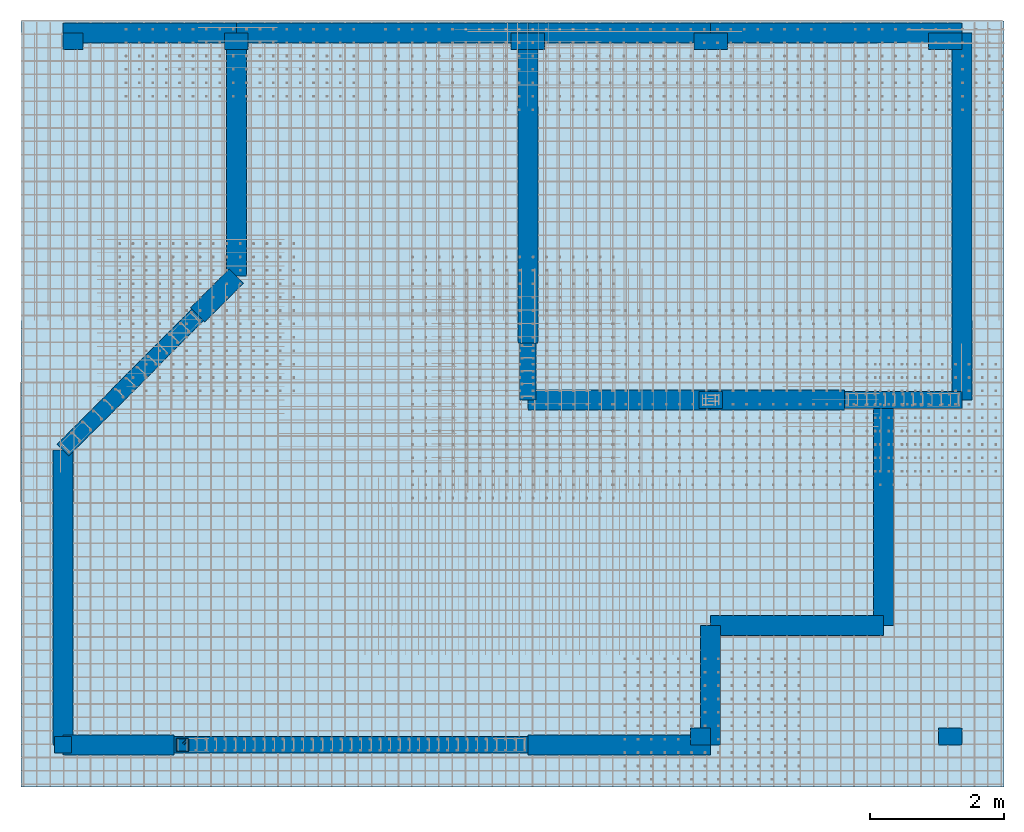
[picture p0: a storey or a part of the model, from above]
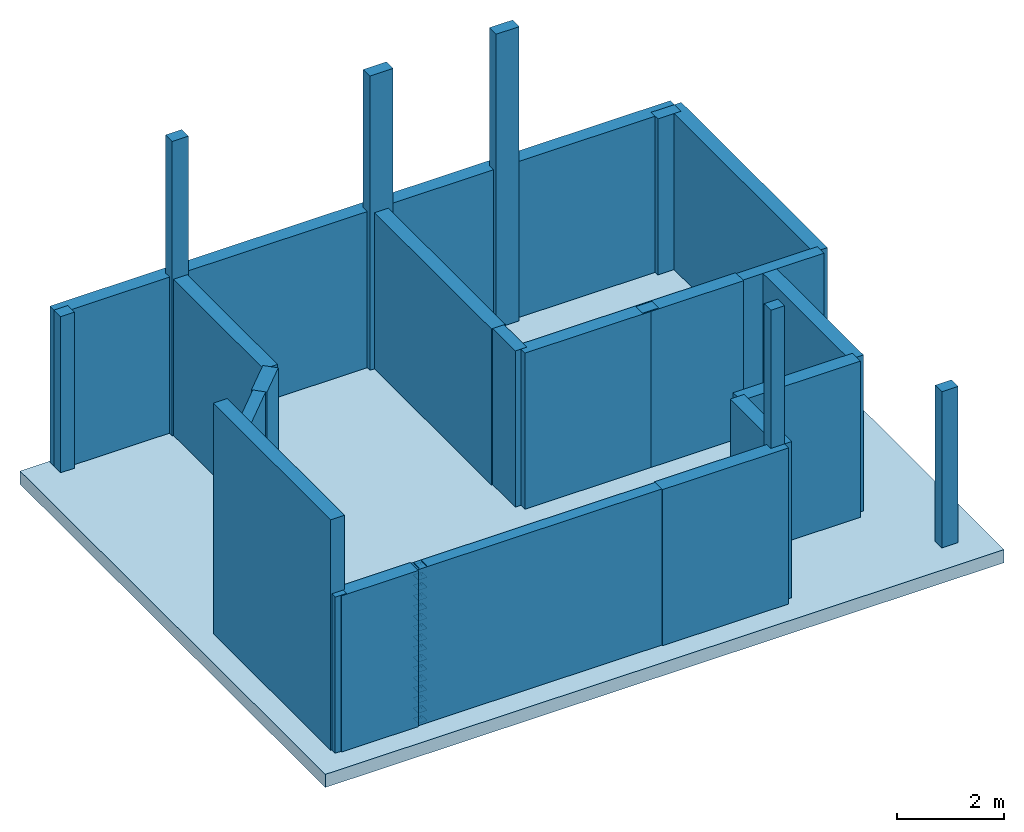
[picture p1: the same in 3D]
Properties of the parts of a building model (IFC4)

# File
Description: ViewDefinition [CoordinationView]
Made in: IFC file generated by ModeSt (Tecnisoft s.a.s.)

# IfcBuildingStorey (3)
In: Abitazione
Name | Elevation (m)
Storey 0 | 0
Storey 1 | 3.57
Storey 2 | 6.73

# IfcBeam: 1 Cr 25x25, 101
In: Storey 1
Type - PredefinedType: BEAM; Material: Calcestruzzo classe C25/30
Description: 1 Cr 25x25 - Cemento armato
Pset_BeamCommon - LoadBearing: yes
BaseQuantities - ?: 0.0625 m2; ?: 0.10375 m3; ?: 1.66 m

# IfcColumn: 2 PL 25x25 principale (2)
Type - PredefinedType: COLUMN; Material: Calcestruzzo classe C25/30
Description: 2 PL 25x25 principale - Cemento armato
Pset_ColumnCommon - LoadBearing: yes
BaseQuantities - ?: 0.0625 m2
Name | In | BaseQuantities, ? (m3) | BaseQuantities, ? (m)
1 | Storey 0 | 0.223125 | 3.57
1 | Storey 1 | 0.106268 | 1.7003

# IfcColumn: 3 PL 25x25 falso (2)
In: Storey 1
Type - PredefinedType: COLUMN; Material: Calcestruzzo classe C25/30
Description: 3 PL 25x25 falso - Cemento armato
Pset_ColumnCommon - LoadBearing: yes
BaseQuantities - ?: 0.0625 m2; ?: 0.1975 m3; ?: 3.16 m
Name
4
6

# IfcColumn: 4 PL 25x30 principale (3)
Type - PredefinedType: COLUMN; Material: Calcestruzzo classe C25/30
Description: 4 PL 25x30 principale - Cemento armato
Pset_ColumnCommon - LoadBearing: yes
BaseQuantities - ?: 0.075 m2
Name | In | BaseQuantities, ? (m3) | BaseQuantities, ? (m)
7 | Storey 0 | 0.26775 | 3.57
2 | Storey 0 | 0.50475 | 6.73
7 | Storey 1 | 0.237 | 3.16

# IfcColumn: 7 PL 25x35 principale (4)
Type - PredefinedType: COLUMN; Material: Calcestruzzo classe C25/30
Description: 7 PL 25x35 principale - Cemento armato
Pset_ColumnCommon - LoadBearing: yes
BaseQuantities - ?: 0.0875 m2
Name | In | BaseQuantities, ? (m3) | BaseQuantities, ? (m)
5 | Storey 0 | 0.312375 | 3.57
3 | Storey 0 | 0.312375 | 3.57
8 | Storey 0 | 0.588875 | 6.73
3 | Storey 1 | 0.2765 | 3.16

# IfcColumn: 8 PL 25x50 principale (4)
Type - PredefinedType: COLUMN; Material: Calcestruzzo classe C25/30
Description: 8 PL 25x50 principale - Cemento armato
Pset_ColumnCommon - LoadBearing: yes
BaseQuantities - ?: 0.125 m2
Name | In | BaseQuantities, ? (m3) | BaseQuantities, ? (m)
11 | Storey 0 | 0.44625 | 3.57
10 | Storey 0 | 0.84125 | 6.73
9 | Storey 0 | 0.84125 | 6.73
11 | Storey 1 | 0.395 | 3.16

# IfcFooting: 1 Platea 30
In: Storey 0
Type - PredefinedType: STRIP_FOOTING
Description: 1 Platea 30; Material: Calcestruzzo classe C25/30 0.3 m
Pset_WallCommon - LoadBearing: yes
BaseQuantities - ?: 50.3818 m3

# IfcReinforcingBar (232)
SteelGrade: B450C
Name | In | NominalDiameter (m) | CrossSectionArea (m2) | BarLength (m)
4 x  | Storey 0 | 0.012 | 0.0001131 | 3.545
3 x  | Storey 0 | 0.012 | 0.0001131 | 0.861822
 | Storey 0 | 0.01 | 0.00007854 | 2.78965
2 x  | Storey 0 | 0.01 | 0.00007854 | 1.16122
 | Storey 0 | 0.01 | 0.00007854 | 5.22
2 x  | Storey 0 | 0.01 | 0.00007854 | 1.16121
 | Storey 0 | 0.016 | 0.00020106 | 3.738
 | Storey 0 | 0.016 | 0.00020106 | 0.857429
 | Storey 0 | 0.01 | 0.00007854 | 0.981776
 | Storey 0 | 0.012 | 0.0001131 | 0.861821
 | Storey 0 | 0.01 | 0.00007854 | 0.79
 | Storey 0 | 0.01 | 0.00007854 | 1.69
3 x  | Storey 1 | 0.012 | 0.0001131 | 3.135
3 x  | Storey 1 | 0.012 | 0.0001131 | 0.811821
 | Storey 1 | 0.012 | 0.0001131 | 1.6753
 | Storey 1 | 0.01 | 0.00007854 | 2.78965
2 x  | Storey 1 | 0.01 | 0.00007854 | 1.16122
 | Storey 1 | 0.01 | 0.00007854 | 1.73161
 | Storey 1 | 0.012 | 0.0001131 | 3.12101
 | Storey 1 | 0.012 | 0.0001131 | 3.09064
 | Storey 1 | 0.012 | 0.0001131 | 3.06027
 | Storey 1 | 0.012 | 0.0001131 | 3.0299
 | Storey 1 | 0.012 | 0.0001131 | 2.99953
 | Storey 1 | 0.012 | 0.0001131 | 2.96916
 | Storey 1 | 0.012 | 0.0001131 | 2.93879
 | Storey 1 | 0.012 | 0.0001131 | 2.90842
 | Storey 1 | 0.012 | 0.0001131 | 2.87805
 | Storey 1 | 0.012 | 0.0001131 | 2.84768
 | Storey 1 | 0.012 | 0.0001131 | 2.81731
 | Storey 1 | 0.012 | 0.0001131 | 2.78694
 | Storey 1 | 0.012 | 0.0001131 | 2.75657
 | Storey 1 | 0.012 | 0.0001131 | 2.7262
 | Storey 1 | 0.012 | 0.0001131 | 2.69583
 | Storey 1 | 0.012 | 0.0001131 | 2.66546
 | Storey 1 | 0.012 | 0.0001131 | 2.63509
 | Storey 1 | 0.012 | 0.0001131 | 2.60472
 | Storey 1 | 0.012 | 0.0001131 | 2.57435
 | Storey 1 | 0.012 | 0.0001131 | 2.54398
 | Storey 1 | 0.012 | 0.0001131 | 2.51361
 | Storey 1 | 0.012 | 0.0001131 | 2.48324
 | Storey 1 | 0.012 | 0.0001131 | 2.45288
 | Storey 1 | 0.012 | 0.0001131 | 2.42251
 | Storey 1 | 0.012 | 0.0001131 | 2.39214
 | Storey 1 | 0.012 | 0.0001131 | 2.36177
 | Storey 1 | 0.012 | 0.0001131 | 2.3314
 | Storey 1 | 0.012 | 0.0001131 | 2.30103
 | Storey 1 | 0.012 | 0.0001131 | 2.27066
 | Storey 1 | 0.012 | 0.0001131 | 2.24029
 | Storey 1 | 0.012 | 0.0001131 | 2.20992
 | Storey 1 | 0.012 | 0.0001131 | 2.17955
 | Storey 1 | 0.012 | 0.0001131 | 2.14918
 | Storey 1 | 0.012 | 0.0001131 | 2.11881
 | Storey 1 | 0.012 | 0.0001131 | 2.08844
 | Storey 1 | 0.012 | 0.0001131 | 2.05807
 | Storey 1 | 0.01 | 0.00007854 | 5.22
 | Storey 1 | 0.01 | 0.00007854 | 1.16121
 | Storey 1 | 0.01 | 0.00007854 | 4.52613
 | Storey 1 | 0.01 | 0.00007854 | 3.39239
 | Storey 1 | 0.01 | 0.00007854 | 2.25865
 | Storey 1 | 0.01 | 0.00007854 | 1.12491
 | Storey 1 | 0.01 | 0.00007854 | 0.79
2 x  | Storey 1 | 0.02 | 0.00031416 | 1.22254
 | Storey 1 | 0.02 | 0.00031416 | 4.78761
 | Storey 1 | 0.016 | 0.00020106 | 1.68472
 | Storey 1 | 0.006 | 0.000028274 | 0.887811
 | Storey 1 | 0.008 | 0.000050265 | 0.898837
6 x  | Storey 1 | 0.022 | 0.00038013 | 1.30034
 | Storey 1 | 0.016 | 0.00020106 | 1.30693
6 x  | Storey 1 | 0.022 | 0.00038013 | 4.45
 | Storey 1 | 0.016 | 0.00020106 | 4.45
 | Storey 1 | 0.022 | 0.00038013 | 3.26284
 | Storey 1 | 0.006 | 0.000028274 | 0.987803
 | Storey 1 | 0.006 | 0.000028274 | 0.402429
 | Storey 1 | 0.02 | 0.00031416 | 4.37
7 x  | Storey 1 | 0.02 | 0.00031416 | 3.26504
 | Storey 1 | 0.008 | 0.000050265 | 0.408429
 | Storey 1 | 0.008 | 0.000050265 | 1.09882
 | Storey 1 | 0.006 | 0.000028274 | 0.773178
2 x  | Storey 1 | 0.006 | 0.000028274 | 1.0878
2 x  | Storey 1 | 0.02 | 0.00031416 | 1.17254
2 x  | Storey 1 | 0.008 | 0.000050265 | 0.898838
 | Storey 0 | 0.02 | 0.00031416 | 1.22254
 | Storey 0 | 0.02 | 0.00031416 | 3.67504
 | Storey 0 | 0.006 | 0.000028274 | 1.0878
4 x  | Storey 1 | 0.016 | 0.00020106 | 3.26943
 | Storey 1 | 0.006 | 0.000028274 | 0.987804
4 x  | Storey 1 | 0.006 | 0.000028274 | 0.40243
3 x  | Storey 1 | 0.006 | 0.000028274 | 1.38779
3 x  | Storey 1 | 0.006 | 0.000028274 | 0.875812
 | Storey 0 | 0.012 | 0.0001131 | 15.0672
 | Storey 0 | 0.012 | 0.0001131 | 11.8272
 | Storey 0 | 0.012 | 0.0001131 | 1.79591
 | Storey 0 | 0.012 | 0.0001131 | 0.437045
 | Storey 0 | 0.012 | 0.0001131 | 3.42591
 | Storey 0 | 0.012 | 0.0001131 | 1.77591
 | Storey 0 | 0.012 | 0.0001131 | 0.995909
 | Storey 0 | 0.012 | 0.0001131 | 1.94591
 | Storey 0 | 0.012 | 0.0001131 | 1.18591
 | Storey 0 | 0.012 | 0.0001131 | 0.915909
 | Storey 0 | 0.012 | 0.0001131 | 1.42591
 | Storey 0 | 0.012 | 0.0001131 | 4.09591
 | Storey 0 | 0.012 | 0.0001131 | 1.45505
 | Storey 0 | 0.012 | 0.0001131 | 1.92591
 | Storey 0 | 0.016 | 0.00020106 | 2.18455
 | Storey 0 | 0.016 | 0.00020106 | 0.582727
 | Storey 0 | 0.012 | 0.0001131 | 1.91591
 | Storey 0 | 0.01 | 0.00007854 | 0.21
 | Storey 0 | 0.03 | 0.00070686 | 0.005
 | Storey 0 | 0.012 | 0.0001131 | 2.57463
 | Storey 0 | 0.012 | 0.0001131 | 1.76232
 | Storey 1 | 0.012 | 0.0001131 | 6.76721
 | Storey 1 | 0.012 | 0.0001131 | 0.496173
 | Storey 1 | 0.012 | 0.0001131 | 0.695183
 | Storey 1 | 0.012 | 0.0001131 | 0.894192
 | Storey 1 | 0.012 | 0.0001131 | 13.7072
 | Storey 1 | 0.012 | 0.0001131 | 6.50716
 | Storey 1 | 0.012 | 0.0001131 | 6.30617
 | Storey 1 | 0.012 | 0.0001131 | 6.10517
 | Storey 1 | 0.012 | 0.0001131 | 5.90418
 | Storey 1 | 0.012 | 0.0001131 | 5.76721
 | Storey 1 | 0.012 | 0.0001131 | 10.9172
 | Storey 1 | 0.012 | 0.0001131 | 0.73963
 | Storey 1 | 0.012 | 0.0001131 | 0.437046
 | Storey 1 | 0.016 | 0.00020106 | 1.72591
 | Storey 1 | 0.016 | 0.00020106 | 0.582727
 | Storey 1 | 0.016 | 0.00020106 | 0.461142
 | Storey 1 | 0.016 | 0.00020106 | 1.83017
 | Storey 1 | 0.016 | 0.00020106 | 2.99591
 | Storey 1 | 0.012 | 0.0001131 | 1.58591
 | Storey 1 | 0.02 | 0.00031416 | 2.86318
 | Storey 1 | 0.02 | 0.00031416 | 0.728409
 | Storey 1 | 0.016 | 0.00020106 | 0.827482
 | Storey 1 | 0.012 | 0.0001131 | 1.39591
 | Storey 1 | 0.016 | 0.00020106 | 1.30591
 | Storey 1 | 0.016 | 0.00020106 | 1.69591
 | Storey 1 | 0.012 | 0.0001131 | 1.36591
 | Storey 1 | 0.012 | 0.0001131 | 0.424888
 | Storey 1 | 0.012 | 0.0001131 | 0.467344
 | Storey 1 | 0.012 | 0.0001131 | 0.876429
 | Storey 1 | 0.012 | 0.0001131 | 0.462548
 | Storey 1 | 0.016 | 0.00020106 | 0.551757
 | Storey 1 | 0.012 | 0.0001131 | 1.09591
 | Storey 1 | 0.012 | 0.0001131 | 1.61591
 | Storey 1 | 0.012 | 0.0001131 | 0.433676
 | Storey 1 | 0.012 | 0.0001131 | 0.858311
 | Storey 1 | 0.012 | 0.0001131 | 0.476277
 | Storey 1 | 0.012 | 0.0001131 | 0.48324
 | Storey 1 | 0.016 | 0.00020106 | 0.881223
 | Storey 1 | 0.012 | 0.0001131 | 0.471284
 | Storey 1 | 0.012 | 0.0001131 | 0.830613
 | Storey 1 | 0.01 | 0.00007854 | 0.16
 | Storey 1 | 0.03 | 0.00070686 | 0.00499988
 | Storey 1 | 0.012 | 0.0001131 | 2.16321
 | Storey 1 | 0.012 | 0.0001131 | 1.4266
 | Storey 1 | 0.012 | 0.0001131 | 1.52661
 | Storey 1 | 0.012 | 0.0001131 | 1.4766
 | Storey 1 | 0.012 | 0.0001131 | 1.42661
 | Storey 1 | 0.012 | 0.0001131 | 2.36321
 | Storey 1 | 0.012 | 0.0001131 | 1.67661
 | Storey 2 | 0.012 | 0.0001131 | 7.15721
 | Storey 2 | 0.012 | 0.0001131 | 7.61721
 | Storey 2 | 0.012 | 0.0001131 | 14.4872
 | Storey 2 | 0.012 | 0.0001131 | 8.18721
 | Storey 2 | 0.012 | 0.0001131 | 5.98721
 | Storey 2 | 0.012 | 0.0001131 | 6.10721
 | Storey 2 | 0.012 | 0.0001131 | 11.7072
 | Storey 2 | 0.012 | 0.0001131 | 9.88721
 | Storey 2 | 0.012 | 0.0001131 | 1.20721
 | Storey 2 | 0.012 | 0.0001131 | 0.603401
 | Storey 2 | 0.012 | 0.0001131 | 1.06591
 | Storey 2 | 0.012 | 0.0001131 | 0.437046
 | Storey 2 | 0.012 | 0.0001131 | 0.885909
 | Storey 2 | 0.012 | 0.0001131 | 1.12591
 | Storey 2 | 0.012 | 0.0001131 | 1.81395
 | Storey 2 | 0.012 | 0.0001131 | 2.11591
 | Storey 2 | 0.012 | 0.0001131 | 0.815909
 | Storey 2 | 0.012 | 0.0001131 | 0.781222
 | Storey 2 | 0.012 | 0.0001131 | 0.783555
 | Storey 2 | 0.012 | 0.0001131 | 0.785886
 | Storey 2 | 0.012 | 0.0001131 | 0.133206
 | Storey 2 | 0.012 | 0.0001131 | 0.955909
 | Storey 2 | 0.012 | 0.0001131 | 0.387218
 | Storey 2 | 0.01 | 0.00007854 | 0.16
 | Storey 2 | 0.03 | 0.00070686 | 0.00500011
 | Storey 1 | 0.016 | 0.00020106 | 6.20721
 | Storey 1 | 0.012 | 0.0001131 | 8.5871
 | Storey 1 | 0.012 | 0.0001131 | 6.23121
 | Storey 1 | 0.01 | 0.00007854 | 8.6051
 | Storey 1 | 0.008 | 0.000050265 | 0.986828
 | Storey 1 | 0.016 | 0.00020106 | 2.30621

# IfcSlab: 2 Soletta (S01) 25
In: Storey 1
Type - PredefinedType: BASESLAB
Description: 2 Soletta (S01) 25; Material: Calcestruzzo classe C25/30 0.25 m
Pset_WallCommon - LoadBearing: yes
BaseQuantities - ?: 35.6637 m3

# IfcSlab: 4 Soletta (C) 25
In: Storey 2
Type - PredefinedType: BASESLAB
Description: 4 Soletta (C) 25; Material: Calcestruzzo classe C25/30 0.25 m
Pset_WallCommon - LoadBearing: yes
BaseQuantities - ?: 40.541 m3

# IfcSlab: 6 Soletta (C) 25 inclinata
In: Storey 1
Type - PredefinedType: BASESLAB
Description: 6 Soletta (C) 25 inclinata; Material: Calcestruzzo classe C25/30 0.25 m
Pset_WallCommon - LoadBearing: yes
BaseQuantities - ?: 94.9916 m3

# IfcWall (30)
Pset_WallCommon - LoadBearing: yes
Name | In | Material
212 | Storey 0 | TAMP 366
101 | Storey 0 | TAMP 366
102 | Storey 0 | TAMP 366
118 | Storey 0 | TAMP 366
104 | Storey 0 | TAMP 366
119 | Storey 0 | TAMP 366
111 | Storey 0 | TAMP 366
109 | Storey 0 | TAMP 366
108 | Storey 0 | TAMP 366
107 | Storey 0 | TAMP 366
113 | Storey 0 | TAMP 366
112 | Storey 0 | TAMP 366
115 | Storey 0 | TAMP 366
105 | Storey 0 | TAMP 240
114 | Storey 0 | TAMP 240
106 | Storey 0 | TAMP 240
201 | Storey 1 | TAMP 366
202 | Storey 1 | TAMP 366
103 | Storey 1 | TAMP 366
211 | Storey 1 | TAMP 366
209 | Storey 1 | TAMP 366
208 | Storey 1 | TAMP 366
207 | Storey 1 | TAMP 366
206 | Storey 1 | TAMP 366
312 | Storey 1 | TAMP 366
215 | Storey 1 | TAMP 366
116 | Storey 1 | TAMP 366
117 | Storey 1 | TAMP 366
204 | Storey 1 | TAMP 135
110 | Storey 1 | TAMP 366

# IfcWall: 7 Parete 25 (2)
In: Storey 1
Type - PredefinedType: STANDARD
Description: 7 Parete 25; Material: Calcestruzzo classe C25/30 0.25 m
Pset_WallCommon - LoadBearing: yes
Name | ? (m3)
 | 15.1802
 | 4.1712

# IfcWallStandardCase: 7 Parete 25 (5)
Type - PredefinedType: STANDARD
Material: Calcestruzzo classe C25/30 0.25 m
Pset_WallCommon - LoadBearing: yes
Name | In | Description | BaseQuantities, ? (m2) | BaseQuantities, ? (m3) | BaseQuantities, ? (m)
110 | Storey 0 | Wall number 110 | 0.4375 | 1.56187 | 3.57
109 | Storey 0 | Wall number 109 | 0.2125 | 0.758625 | 3.57
108 | Storey 0 | Wall number 108 | 1.32 | 4.7124 | 3.57
107 | Storey 0 | Wall number 107 | 0.712412 | 2.54331 | 3.57
210 | Storey 1 | Wall number 210 | 0.2125 | 0.6715 | 3.16

# IfcReinforcingBarType, no part of this type: type
PredefinedType: MAIN; NominalDiameter: 0.012 m; CrossSectionArea: 0.0001131 m2; BarLength: 3.545 m; Material: Steel

# IfcReinforcingBarType, no part of this type: type
PredefinedType: MAIN; NominalDiameter: 0.012 m; CrossSectionArea: 0.0001131 m2; BarLength: 0.861822 m; Material: Steel

# IfcReinforcingBarType, no part of this type: type
PredefinedType: LIGATURE; NominalDiameter: 0.01 m; CrossSectionArea: 0.00007854 m2; BarLength: 2.78965 m; Material: Steel

# IfcReinforcingBarType, no part of this type: type
PredefinedType: LIGATURE; NominalDiameter: 0.01 m; CrossSectionArea: 0.00007854 m2; BarLength: 1.16122 m; Material: Steel

# IfcReinforcingBarType, no part of this type: type
PredefinedType: MAIN; NominalDiameter: 0.012 m; CrossSectionArea: 0.0001131 m2; BarLength: 3.545 m; Material: Steel

# IfcReinforcingBarType, no part of this type: type
PredefinedType: MAIN; NominalDiameter: 0.012 m; CrossSectionArea: 0.0001131 m2; BarLength: 0.861822 m; Material: Steel

# IfcReinforcingBarType, no part of this type: type
PredefinedType: LIGATURE; NominalDiameter: 0.01 m; CrossSectionArea: 0.00007854 m2; BarLength: 5.22 m; Material: Steel

# IfcReinforcingBarType, no part of this type: type
PredefinedType: LIGATURE; NominalDiameter: 0.01 m; CrossSectionArea: 0.00007854 m2; BarLength: 1.16121 m; Material: Steel

# IfcReinforcingBarType, no part of this type: type
PredefinedType: MAIN; NominalDiameter: 0.016 m; CrossSectionArea: 0.00020106 m2; BarLength: 3.738 m; Material: Steel

# IfcReinforcingBarType, no part of this type: type
PredefinedType: MAIN; NominalDiameter: 0.016 m; CrossSectionArea: 0.00020106 m2; BarLength: 0.857429 m; Material: Steel

# IfcReinforcingBarType, no part of this type: type
PredefinedType: LIGATURE; NominalDiameter: 0.01 m; CrossSectionArea: 0.00007854 m2; BarLength: 0.981776 m; Material: Steel

# IfcReinforcingBarType, no part of this type: type
PredefinedType: MAIN; NominalDiameter: 0.012 m; CrossSectionArea: 0.0001131 m2; BarLength: 3.545 m; Material: Steel

# IfcReinforcingBarType, no part of this type: type
PredefinedType: MAIN; NominalDiameter: 0.012 m; CrossSectionArea: 0.0001131 m2; BarLength: 0.861821 m; Material: Steel

# IfcReinforcingBarType, no part of this type: type
PredefinedType: LIGATURE; NominalDiameter: 0.01 m; CrossSectionArea: 0.00007854 m2; BarLength: 0.79 m; Material: Steel

# IfcReinforcingBarType, no part of this type: type
PredefinedType: LIGATURE; NominalDiameter: 0.01 m; CrossSectionArea: 0.00007854 m2; BarLength: 1.16122 m; Material: Steel

# IfcReinforcingBarType, no part of this type: type
PredefinedType: MAIN; NominalDiameter: 0.012 m; CrossSectionArea: 0.0001131 m2; BarLength: 3.545 m; Material: Steel

# IfcReinforcingBarType, no part of this type: type
PredefinedType: MAIN; NominalDiameter: 0.012 m; CrossSectionArea: 0.0001131 m2; BarLength: 0.861822 m; Material: Steel

# IfcReinforcingBarType, no part of this type: type
PredefinedType: LIGATURE; NominalDiameter: 0.01 m; CrossSectionArea: 0.00007854 m2; BarLength: 1.69 m; Material: Steel

# IfcReinforcingBarType, no part of this type: type
PredefinedType: LIGATURE; NominalDiameter: 0.01 m; CrossSectionArea: 0.00007854 m2; BarLength: 1.16121 m; Material: Steel

# IfcReinforcingBarType, no part of this type: type
PredefinedType: MAIN; NominalDiameter: 0.012 m; CrossSectionArea: 0.0001131 m2; BarLength: 3.135 m; Material: Steel

# IfcReinforcingBarType, no part of this type: type
PredefinedType: MAIN; NominalDiameter: 0.012 m; CrossSectionArea: 0.0001131 m2; BarLength: 0.811821 m; Material: Steel

# IfcReinforcingBarType, no part of this type: type
PredefinedType: MAIN; NominalDiameter: 0.012 m; CrossSectionArea: 0.0001131 m2; BarLength: 1.6753 m; Material: Steel

# IfcReinforcingBarType, no part of this type: type
PredefinedType: LIGATURE; NominalDiameter: 0.01 m; CrossSectionArea: 0.00007854 m2; BarLength: 2.78965 m; Material: Steel

# IfcReinforcingBarType, no part of this type: type
PredefinedType: LIGATURE; NominalDiameter: 0.01 m; CrossSectionArea: 0.00007854 m2; BarLength: 1.16122 m; Material: Steel

# IfcReinforcingBarType, no part of this type: type
PredefinedType: LIGATURE; NominalDiameter: 0.01 m; CrossSectionArea: 0.00007854 m2; BarLength: 1.73161 m; Material: Steel

# IfcReinforcingBarType, no part of this type: type
PredefinedType: MAIN; NominalDiameter: 0.012 m; CrossSectionArea: 0.0001131 m2; BarLength: 3.135 m; Material: Steel

# IfcReinforcingBarType, no part of this type: type
PredefinedType: MAIN; NominalDiameter: 0.012 m; CrossSectionArea: 0.0001131 m2; BarLength: 0.811821 m; Material: Steel

# IfcReinforcingBarType, no part of this type: type
PredefinedType: MAIN; NominalDiameter: 0.012 m; CrossSectionArea: 0.0001131 m2; BarLength: 3.12101 m; Material: Steel

# IfcReinforcingBarType, no part of this type: type
PredefinedType: MAIN; NominalDiameter: 0.012 m; CrossSectionArea: 0.0001131 m2; BarLength: 3.09064 m; Material: Steel

# IfcReinforcingBarType, no part of this type: type
PredefinedType: MAIN; NominalDiameter: 0.012 m; CrossSectionArea: 0.0001131 m2; BarLength: 3.06027 m; Material: Steel

# IfcReinforcingBarType, no part of this type: type
PredefinedType: MAIN; NominalDiameter: 0.012 m; CrossSectionArea: 0.0001131 m2; BarLength: 3.0299 m; Material: Steel

# IfcReinforcingBarType, no part of this type: type
PredefinedType: MAIN; NominalDiameter: 0.012 m; CrossSectionArea: 0.0001131 m2; BarLength: 2.99953 m; Material: Steel

# IfcReinforcingBarType, no part of this type: type
PredefinedType: MAIN; NominalDiameter: 0.012 m; CrossSectionArea: 0.0001131 m2; BarLength: 2.96916 m; Material: Steel

# IfcReinforcingBarType, no part of this type: type
PredefinedType: MAIN; NominalDiameter: 0.012 m; CrossSectionArea: 0.0001131 m2; BarLength: 2.93879 m; Material: Steel

# IfcReinforcingBarType, no part of this type: type
PredefinedType: MAIN; NominalDiameter: 0.012 m; CrossSectionArea: 0.0001131 m2; BarLength: 2.90842 m; Material: Steel

# IfcReinforcingBarType, no part of this type: type
PredefinedType: MAIN; NominalDiameter: 0.012 m; CrossSectionArea: 0.0001131 m2; BarLength: 2.87805 m; Material: Steel

# IfcReinforcingBarType, no part of this type: type
PredefinedType: MAIN; NominalDiameter: 0.012 m; CrossSectionArea: 0.0001131 m2; BarLength: 2.84768 m; Material: Steel

# IfcReinforcingBarType, no part of this type: type
PredefinedType: MAIN; NominalDiameter: 0.012 m; CrossSectionArea: 0.0001131 m2; BarLength: 2.81731 m; Material: Steel

# IfcReinforcingBarType, no part of this type: type
PredefinedType: MAIN; NominalDiameter: 0.012 m; CrossSectionArea: 0.0001131 m2; BarLength: 2.78694 m; Material: Steel

# IfcReinforcingBarType, no part of this type: type
PredefinedType: MAIN; NominalDiameter: 0.012 m; CrossSectionArea: 0.0001131 m2; BarLength: 2.75657 m; Material: Steel

# IfcReinforcingBarType, no part of this type: type
PredefinedType: MAIN; NominalDiameter: 0.012 m; CrossSectionArea: 0.0001131 m2; BarLength: 2.7262 m; Material: Steel

# IfcReinforcingBarType, no part of this type: type
PredefinedType: MAIN; NominalDiameter: 0.012 m; CrossSectionArea: 0.0001131 m2; BarLength: 2.69583 m; Material: Steel

# IfcReinforcingBarType, no part of this type: type
PredefinedType: MAIN; NominalDiameter: 0.012 m; CrossSectionArea: 0.0001131 m2; BarLength: 2.66546 m; Material: Steel

# IfcReinforcingBarType, no part of this type: type
PredefinedType: MAIN; NominalDiameter: 0.012 m; CrossSectionArea: 0.0001131 m2; BarLength: 2.63509 m; Material: Steel

# IfcReinforcingBarType, no part of this type: type
PredefinedType: MAIN; NominalDiameter: 0.012 m; CrossSectionArea: 0.0001131 m2; BarLength: 2.60472 m; Material: Steel

# IfcReinforcingBarType, no part of this type: type
PredefinedType: MAIN; NominalDiameter: 0.012 m; CrossSectionArea: 0.0001131 m2; BarLength: 2.57435 m; Material: Steel

# IfcReinforcingBarType, no part of this type: type
PredefinedType: MAIN; NominalDiameter: 0.012 m; CrossSectionArea: 0.0001131 m2; BarLength: 2.54398 m; Material: Steel

# IfcReinforcingBarType, no part of this type: type
PredefinedType: MAIN; NominalDiameter: 0.012 m; CrossSectionArea: 0.0001131 m2; BarLength: 2.51361 m; Material: Steel

# IfcReinforcingBarType, no part of this type: type
PredefinedType: MAIN; NominalDiameter: 0.012 m; CrossSectionArea: 0.0001131 m2; BarLength: 2.48324 m; Material: Steel

# IfcReinforcingBarType, no part of this type: type
PredefinedType: MAIN; NominalDiameter: 0.012 m; CrossSectionArea: 0.0001131 m2; BarLength: 2.45288 m; Material: Steel

# IfcReinforcingBarType, no part of this type: type
PredefinedType: MAIN; NominalDiameter: 0.012 m; CrossSectionArea: 0.0001131 m2; BarLength: 2.42251 m; Material: Steel

# IfcReinforcingBarType, no part of this type: type
PredefinedType: MAIN; NominalDiameter: 0.012 m; CrossSectionArea: 0.0001131 m2; BarLength: 2.39214 m; Material: Steel

# IfcReinforcingBarType, no part of this type: type
PredefinedType: MAIN; NominalDiameter: 0.012 m; CrossSectionArea: 0.0001131 m2; BarLength: 2.36177 m; Material: Steel

# IfcReinforcingBarType, no part of this type: type
PredefinedType: MAIN; NominalDiameter: 0.012 m; CrossSectionArea: 0.0001131 m2; BarLength: 2.3314 m; Material: Steel

# IfcReinforcingBarType, no part of this type: type
PredefinedType: MAIN; NominalDiameter: 0.012 m; CrossSectionArea: 0.0001131 m2; BarLength: 2.30103 m; Material: Steel

# IfcReinforcingBarType, no part of this type: type
PredefinedType: MAIN; NominalDiameter: 0.012 m; CrossSectionArea: 0.0001131 m2; BarLength: 2.27066 m; Material: Steel

# IfcReinforcingBarType, no part of this type: type
PredefinedType: MAIN; NominalDiameter: 0.012 m; CrossSectionArea: 0.0001131 m2; BarLength: 2.24029 m; Material: Steel

# IfcReinforcingBarType, no part of this type: type
PredefinedType: MAIN; NominalDiameter: 0.012 m; CrossSectionArea: 0.0001131 m2; BarLength: 2.20992 m; Material: Steel

# IfcReinforcingBarType, no part of this type: type
PredefinedType: MAIN; NominalDiameter: 0.012 m; CrossSectionArea: 0.0001131 m2; BarLength: 2.17955 m; Material: Steel

# IfcReinforcingBarType, no part of this type: type
PredefinedType: MAIN; NominalDiameter: 0.012 m; CrossSectionArea: 0.0001131 m2; BarLength: 2.14918 m; Material: Steel

# IfcReinforcingBarType, no part of this type: type
PredefinedType: MAIN; NominalDiameter: 0.012 m; CrossSectionArea: 0.0001131 m2; BarLength: 2.11881 m; Material: Steel

# IfcReinforcingBarType, no part of this type: type
PredefinedType: MAIN; NominalDiameter: 0.012 m; CrossSectionArea: 0.0001131 m2; BarLength: 2.08844 m; Material: Steel

# IfcReinforcingBarType, no part of this type: type
PredefinedType: MAIN; NominalDiameter: 0.012 m; CrossSectionArea: 0.0001131 m2; BarLength: 2.05807 m; Material: Steel

# IfcReinforcingBarType, no part of this type: type
PredefinedType: LIGATURE; NominalDiameter: 0.01 m; CrossSectionArea: 0.00007854 m2; BarLength: 5.22 m; Material: Steel

# IfcReinforcingBarType, no part of this type: type
PredefinedType: LIGATURE; NominalDiameter: 0.01 m; CrossSectionArea: 0.00007854 m2; BarLength: 1.16121 m; Material: Steel

# IfcReinforcingBarType, no part of this type: type
PredefinedType: LIGATURE; NominalDiameter: 0.01 m; CrossSectionArea: 0.00007854 m2; BarLength: 4.52613 m; Material: Steel

# IfcReinforcingBarType, no part of this type: type
PredefinedType: LIGATURE; NominalDiameter: 0.01 m; CrossSectionArea: 0.00007854 m2; BarLength: 3.39239 m; Material: Steel

# IfcReinforcingBarType, no part of this type: type
PredefinedType: LIGATURE; NominalDiameter: 0.01 m; CrossSectionArea: 0.00007854 m2; BarLength: 2.25865 m; Material: Steel

# IfcReinforcingBarType, no part of this type: type
PredefinedType: LIGATURE; NominalDiameter: 0.01 m; CrossSectionArea: 0.00007854 m2; BarLength: 1.12491 m; Material: Steel

# IfcReinforcingBarType, no part of this type: type
PredefinedType: MAIN; NominalDiameter: 0.012 m; CrossSectionArea: 0.0001131 m2; BarLength: 3.135 m; Material: Steel

# IfcReinforcingBarType, no part of this type: type
PredefinedType: MAIN; NominalDiameter: 0.012 m; CrossSectionArea: 0.0001131 m2; BarLength: 0.811821 m; Material: Steel

# IfcReinforcingBarType, no part of this type: type
PredefinedType: LIGATURE; NominalDiameter: 0.01 m; CrossSectionArea: 0.00007854 m2; BarLength: 0.79 m; Material: Steel

# IfcReinforcingBarType, no part of this type: type
PredefinedType: LIGATURE; NominalDiameter: 0.01 m; CrossSectionArea: 0.00007854 m2; BarLength: 1.16122 m; Material: Steel

# IfcReinforcingBarType, no part of this type: type
PredefinedType: MAIN; NominalDiameter: 0.02 m; CrossSectionArea: 0.00031416 m2; BarLength: 1.22254 m; Material: Steel

# IfcReinforcingBarType, no part of this type: type
PredefinedType: MAIN; NominalDiameter: 0.02 m; CrossSectionArea: 0.00031416 m2; BarLength: 4.78761 m; Material: Steel

# IfcReinforcingBarType, no part of this type: type
PredefinedType: MAIN; NominalDiameter: 0.016 m; CrossSectionArea: 0.00020106 m2; BarLength: 1.68472 m; Material: Steel

# IfcReinforcingBarType, no part of this type: type
PredefinedType: LIGATURE; NominalDiameter: 0.006 m; CrossSectionArea: 0.000028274 m2; BarLength: 0.887811 m; Material: Steel

# IfcReinforcingBarType, no part of this type: type
PredefinedType: LIGATURE; NominalDiameter: 0.008 m; CrossSectionArea: 0.000050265 m2; BarLength: 0.898837 m; Material: Steel

# IfcReinforcingBarType, no part of this type: type
PredefinedType: MAIN; NominalDiameter: 0.022 m; CrossSectionArea: 0.00038013 m2; BarLength: 1.30034 m; Material: Steel

# IfcReinforcingBarType, no part of this type: type
PredefinedType: MAIN; NominalDiameter: 0.016 m; CrossSectionArea: 0.00020106 m2; BarLength: 1.30693 m; Material: Steel

# IfcReinforcingBarType, no part of this type: type
PredefinedType: MAIN; NominalDiameter: 0.022 m; CrossSectionArea: 0.00038013 m2; BarLength: 4.45 m; Material: Steel

# IfcReinforcingBarType, no part of this type: type
PredefinedType: MAIN; NominalDiameter: 0.016 m; CrossSectionArea: 0.00020106 m2; BarLength: 4.45 m; Material: Steel

# IfcReinforcingBarType, no part of this type: type
PredefinedType: MAIN; NominalDiameter: 0.022 m; CrossSectionArea: 0.00038013 m2; BarLength: 3.26284 m; Material: Steel

# IfcReinforcingBarType, no part of this type: type
PredefinedType: LIGATURE; NominalDiameter: 0.006 m; CrossSectionArea: 0.000028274 m2; BarLength: 0.987803 m; Material: Steel

# IfcReinforcingBarType, no part of this type: type
PredefinedType: LIGATURE; NominalDiameter: 0.006 m; CrossSectionArea: 0.000028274 m2; BarLength: 0.402429 m; Material: Steel

# IfcReinforcingBarType, no part of this type: type
PredefinedType: MAIN; NominalDiameter: 0.02 m; CrossSectionArea: 0.00031416 m2; BarLength: 1.22254 m; Material: Steel

# IfcReinforcingBarType, no part of this type: type
PredefinedType: MAIN; NominalDiameter: 0.02 m; CrossSectionArea: 0.00031416 m2; BarLength: 4.37 m; Material: Steel

# IfcReinforcingBarType, no part of this type: type
PredefinedType: MAIN; NominalDiameter: 0.02 m; CrossSectionArea: 0.00031416 m2; BarLength: 3.26504 m; Material: Steel

# IfcReinforcingBarType, no part of this type: type
PredefinedType: LIGATURE; NominalDiameter: 0.008 m; CrossSectionArea: 0.000050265 m2; BarLength: 0.408429 m; Material: Steel

# IfcReinforcingBarType, no part of this type: type
PredefinedType: LIGATURE; NominalDiameter: 0.008 m; CrossSectionArea: 0.000050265 m2; BarLength: 1.09882 m; Material: Steel

# IfcReinforcingBarType, no part of this type: type
PredefinedType: LIGATURE; NominalDiameter: 0.006 m; CrossSectionArea: 0.000028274 m2; BarLength: 0.773178 m; Material: Steel

# IfcReinforcingBarType, no part of this type: type
PredefinedType: LIGATURE; NominalDiameter: 0.006 m; CrossSectionArea: 0.000028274 m2; BarLength: 1.0878 m; Material: Steel

# IfcReinforcingBarType, no part of this type: type
PredefinedType: MAIN; NominalDiameter: 0.02 m; CrossSectionArea: 0.00031416 m2; BarLength: 1.17254 m; Material: Steel

# IfcReinforcingBarType, no part of this type: type
PredefinedType: MAIN; NominalDiameter: 0.02 m; CrossSectionArea: 0.00031416 m2; BarLength: 3.26504 m; Material: Steel

# IfcReinforcingBarType, no part of this type: type
PredefinedType: LIGATURE; NominalDiameter: 0.008 m; CrossSectionArea: 0.000050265 m2; BarLength: 0.898838 m; Material: Steel

# IfcReinforcingBarType, no part of this type: type
PredefinedType: MAIN; NominalDiameter: 0.02 m; CrossSectionArea: 0.00031416 m2; BarLength: 1.22254 m; Material: Steel

# IfcReinforcingBarType, no part of this type: type
PredefinedType: MAIN; NominalDiameter: 0.02 m; CrossSectionArea: 0.00031416 m2; BarLength: 3.67504 m; Material: Steel

# IfcReinforcingBarType, no part of this type: type
PredefinedType: LIGATURE; NominalDiameter: 0.006 m; CrossSectionArea: 0.000028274 m2; BarLength: 1.0878 m; Material: Steel

# IfcReinforcingBarType, no part of this type: type
PredefinedType: MAIN; NominalDiameter: 0.02 m; CrossSectionArea: 0.00031416 m2; BarLength: 1.17254 m; Material: Steel

# IfcReinforcingBarType, no part of this type: type
PredefinedType: MAIN; NominalDiameter: 0.02 m; CrossSectionArea: 0.00031416 m2; BarLength: 3.26504 m; Material: Steel

# IfcReinforcingBarType, no part of this type: type
PredefinedType: LIGATURE; NominalDiameter: 0.008 m; CrossSectionArea: 0.000050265 m2; BarLength: 0.898838 m; Material: Steel

# IfcReinforcingBarType, no part of this type: type
PredefinedType: MAIN; NominalDiameter: 0.022 m; CrossSectionArea: 0.00038013 m2; BarLength: 1.30034 m; Material: Steel

# IfcReinforcingBarType, no part of this type: type
PredefinedType: MAIN; NominalDiameter: 0.022 m; CrossSectionArea: 0.00038013 m2; BarLength: 4.45 m; Material: Steel

# IfcReinforcingBarType, no part of this type: type
PredefinedType: MAIN; NominalDiameter: 0.016 m; CrossSectionArea: 0.00020106 m2; BarLength: 3.26943 m; Material: Steel

# IfcReinforcingBarType, no part of this type: type
PredefinedType: LIGATURE; NominalDiameter: 0.006 m; CrossSectionArea: 0.000028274 m2; BarLength: 0.987804 m; Material: Steel

# IfcReinforcingBarType, no part of this type: type
PredefinedType: MAIN; NominalDiameter: 0.022 m; CrossSectionArea: 0.00038013 m2; BarLength: 1.30034 m; Material: Steel

# IfcReinforcingBarType, no part of this type: type
PredefinedType: MAIN; NominalDiameter: 0.022 m; CrossSectionArea: 0.00038013 m2; BarLength: 4.45 m; Material: Steel

# IfcReinforcingBarType, no part of this type: type
PredefinedType: MAIN; NominalDiameter: 0.02 m; CrossSectionArea: 0.00031416 m2; BarLength: 3.26504 m; Material: Steel

# IfcReinforcingBarType, no part of this type: type
PredefinedType: LIGATURE; NominalDiameter: 0.006 m; CrossSectionArea: 0.000028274 m2; BarLength: 1.0878 m; Material: Steel

# IfcReinforcingBarType, no part of this type: type
PredefinedType: LIGATURE; NominalDiameter: 0.006 m; CrossSectionArea: 0.000028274 m2; BarLength: 0.40243 m; Material: Steel

# IfcReinforcingBarType, no part of this type: type
PredefinedType: MAIN; NominalDiameter: 0.022 m; CrossSectionArea: 0.00038013 m2; BarLength: 1.30034 m; Material: Steel

# IfcReinforcingBarType, no part of this type: type
PredefinedType: MAIN; NominalDiameter: 0.022 m; CrossSectionArea: 0.00038013 m2; BarLength: 4.45 m; Material: Steel

# IfcReinforcingBarType, no part of this type: type
PredefinedType: MAIN; NominalDiameter: 0.02 m; CrossSectionArea: 0.00031416 m2; BarLength: 3.26504 m; Material: Steel

# IfcReinforcingBarType, no part of this type: type
PredefinedType: MAIN; NominalDiameter: 0.016 m; CrossSectionArea: 0.00020106 m2; BarLength: 3.26943 m; Material: Steel

# IfcReinforcingBarType, no part of this type: type
PredefinedType: LIGATURE; NominalDiameter: 0.006 m; CrossSectionArea: 0.000028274 m2; BarLength: 0.40243 m; Material: Steel

# IfcReinforcingBarType, no part of this type: type
PredefinedType: LIGATURE; NominalDiameter: 0.006 m; CrossSectionArea: 0.000028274 m2; BarLength: 1.38779 m; Material: Steel

# IfcReinforcingBarType, no part of this type: type
PredefinedType: LIGATURE; NominalDiameter: 0.006 m; CrossSectionArea: 0.000028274 m2; BarLength: 0.875812 m; Material: Steel

# IfcReinforcingBarType, no part of this type: type
PredefinedType: MAIN; NominalDiameter: 0.022 m; CrossSectionArea: 0.00038013 m2; BarLength: 1.30034 m; Material: Steel

# IfcReinforcingBarType, no part of this type: type
PredefinedType: MAIN; NominalDiameter: 0.022 m; CrossSectionArea: 0.00038013 m2; BarLength: 4.45 m; Material: Steel

# IfcReinforcingBarType, no part of this type: type
PredefinedType: MAIN; NominalDiameter: 0.02 m; CrossSectionArea: 0.00031416 m2; BarLength: 3.26504 m; Material: Steel

# IfcReinforcingBarType, no part of this type: type
PredefinedType: MAIN; NominalDiameter: 0.016 m; CrossSectionArea: 0.00020106 m2; BarLength: 3.26943 m; Material: Steel

# IfcReinforcingBarType, no part of this type: type
PredefinedType: LIGATURE; NominalDiameter: 0.006 m; CrossSectionArea: 0.000028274 m2; BarLength: 0.40243 m; Material: Steel

# IfcReinforcingBarType, no part of this type: type
PredefinedType: LIGATURE; NominalDiameter: 0.006 m; CrossSectionArea: 0.000028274 m2; BarLength: 1.38779 m; Material: Steel

# IfcReinforcingBarType, no part of this type: type
PredefinedType: LIGATURE; NominalDiameter: 0.006 m; CrossSectionArea: 0.000028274 m2; BarLength: 0.875812 m; Material: Steel

# IfcReinforcingBarType, no part of this type: type
PredefinedType: MAIN; NominalDiameter: 0.022 m; CrossSectionArea: 0.00038013 m2; BarLength: 1.30034 m; Material: Steel

# IfcReinforcingBarType, no part of this type: type
PredefinedType: MAIN; NominalDiameter: 0.022 m; CrossSectionArea: 0.00038013 m2; BarLength: 4.45 m; Material: Steel

# IfcReinforcingBarType, no part of this type: type
PredefinedType: MAIN; NominalDiameter: 0.02 m; CrossSectionArea: 0.00031416 m2; BarLength: 3.26504 m; Material: Steel

# IfcReinforcingBarType, no part of this type: type
PredefinedType: MAIN; NominalDiameter: 0.016 m; CrossSectionArea: 0.00020106 m2; BarLength: 3.26943 m; Material: Steel

# IfcReinforcingBarType, no part of this type: type
PredefinedType: LIGATURE; NominalDiameter: 0.006 m; CrossSectionArea: 0.000028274 m2; BarLength: 1.38779 m; Material: Steel

# IfcReinforcingBarType, no part of this type: type
PredefinedType: LIGATURE; NominalDiameter: 0.006 m; CrossSectionArea: 0.000028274 m2; BarLength: 0.40243 m; Material: Steel

# IfcReinforcingBarType, no part of this type: type
PredefinedType: LIGATURE; NominalDiameter: 0.006 m; CrossSectionArea: 0.000028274 m2; BarLength: 0.875812 m; Material: Steel

# IfcReinforcingBarType, no part of this type: type
PredefinedType: MAIN; NominalDiameter: 0.012 m; CrossSectionArea: 0.0001131 m2; BarLength: 15.0672 m; Material: Steel

# IfcReinforcingBarType, no part of this type: type
PredefinedType: MAIN; NominalDiameter: 0.012 m; CrossSectionArea: 0.0001131 m2; BarLength: 11.8272 m; Material: Steel

# IfcReinforcingBarType, no part of this type: type
PredefinedType: MAIN; NominalDiameter: 0.012 m; CrossSectionArea: 0.0001131 m2; BarLength: 1.79591 m; Material: Steel

# IfcReinforcingBarType, no part of this type: type
PredefinedType: MAIN; NominalDiameter: 0.012 m; CrossSectionArea: 0.0001131 m2; BarLength: 0.437045 m; Material: Steel

# IfcReinforcingBarType, no part of this type: type
PredefinedType: MAIN; NominalDiameter: 0.012 m; CrossSectionArea: 0.0001131 m2; BarLength: 3.42591 m; Material: Steel

# IfcReinforcingBarType, no part of this type: type
PredefinedType: MAIN; NominalDiameter: 0.012 m; CrossSectionArea: 0.0001131 m2; BarLength: 1.77591 m; Material: Steel

# IfcReinforcingBarType, no part of this type: type
PredefinedType: MAIN; NominalDiameter: 0.012 m; CrossSectionArea: 0.0001131 m2; BarLength: 0.995909 m; Material: Steel

# IfcReinforcingBarType, no part of this type: type
PredefinedType: MAIN; NominalDiameter: 0.012 m; CrossSectionArea: 0.0001131 m2; BarLength: 1.94591 m; Material: Steel

# IfcReinforcingBarType, no part of this type: type
PredefinedType: MAIN; NominalDiameter: 0.012 m; CrossSectionArea: 0.0001131 m2; BarLength: 1.18591 m; Material: Steel

# IfcReinforcingBarType, no part of this type: type
PredefinedType: MAIN; NominalDiameter: 0.012 m; CrossSectionArea: 0.0001131 m2; BarLength: 0.915909 m; Material: Steel

# IfcReinforcingBarType, no part of this type: type
PredefinedType: MAIN; NominalDiameter: 0.012 m; CrossSectionArea: 0.0001131 m2; BarLength: 1.42591 m; Material: Steel

# IfcReinforcingBarType, no part of this type: type
PredefinedType: MAIN; NominalDiameter: 0.012 m; CrossSectionArea: 0.0001131 m2; BarLength: 4.09591 m; Material: Steel

# IfcReinforcingBarType, no part of this type: type
PredefinedType: MAIN; NominalDiameter: 0.012 m; CrossSectionArea: 0.0001131 m2; BarLength: 1.45505 m; Material: Steel

# IfcReinforcingBarType, no part of this type: type
PredefinedType: MAIN; NominalDiameter: 0.012 m; CrossSectionArea: 0.0001131 m2; BarLength: 1.92591 m; Material: Steel

# IfcReinforcingBarType, no part of this type: type
PredefinedType: MAIN; NominalDiameter: 0.016 m; CrossSectionArea: 0.00020106 m2; BarLength: 2.18455 m; Material: Steel

# IfcReinforcingBarType, no part of this type: type
PredefinedType: MAIN; NominalDiameter: 0.016 m; CrossSectionArea: 0.00020106 m2; BarLength: 0.582727 m; Material: Steel

# IfcReinforcingBarType, no part of this type: type
PredefinedType: MAIN; NominalDiameter: 0.012 m; CrossSectionArea: 0.0001131 m2; BarLength: 1.91591 m; Material: Steel

# IfcReinforcingBarType, no part of this type: type
PredefinedType: MAIN; NominalDiameter: 0.01 m; CrossSectionArea: 0.00007854 m2; BarLength: 0.21 m; Material: Steel

# IfcReinforcingBarType, no part of this type: type
PredefinedType: MAIN; NominalDiameter: 0.03 m; CrossSectionArea: 0.00070686 m2; BarLength: 0.005 m; Material: Steel

# IfcReinforcingBarType, no part of this type: type
PredefinedType: MAIN; NominalDiameter: 0.012 m; CrossSectionArea: 0.0001131 m2; BarLength: 2.57463 m; Material: Steel

# IfcReinforcingBarType, no part of this type: type
PredefinedType: MAIN; NominalDiameter: 0.012 m; CrossSectionArea: 0.0001131 m2; BarLength: 1.76232 m; Material: Steel

# IfcReinforcingBarType, no part of this type: type
PredefinedType: MAIN; NominalDiameter: 0.012 m; CrossSectionArea: 0.0001131 m2; BarLength: 6.76721 m; Material: Steel

# IfcReinforcingBarType, no part of this type: type
PredefinedType: MAIN; NominalDiameter: 0.012 m; CrossSectionArea: 0.0001131 m2; BarLength: 0.496173 m; Material: Steel

# IfcReinforcingBarType, no part of this type: type
PredefinedType: MAIN; NominalDiameter: 0.012 m; CrossSectionArea: 0.0001131 m2; BarLength: 0.695183 m; Material: Steel

# IfcReinforcingBarType, no part of this type: type
PredefinedType: MAIN; NominalDiameter: 0.012 m; CrossSectionArea: 0.0001131 m2; BarLength: 0.894192 m; Material: Steel

# IfcReinforcingBarType, no part of this type: type
PredefinedType: MAIN; NominalDiameter: 0.012 m; CrossSectionArea: 0.0001131 m2; BarLength: 13.7072 m; Material: Steel

# IfcReinforcingBarType, no part of this type: type
PredefinedType: MAIN; NominalDiameter: 0.012 m; CrossSectionArea: 0.0001131 m2; BarLength: 6.50716 m; Material: Steel

# IfcReinforcingBarType, no part of this type: type
PredefinedType: MAIN; NominalDiameter: 0.012 m; CrossSectionArea: 0.0001131 m2; BarLength: 6.30617 m; Material: Steel

# IfcReinforcingBarType, no part of this type: type
PredefinedType: MAIN; NominalDiameter: 0.012 m; CrossSectionArea: 0.0001131 m2; BarLength: 6.10517 m; Material: Steel

# IfcReinforcingBarType, no part of this type: type
PredefinedType: MAIN; NominalDiameter: 0.012 m; CrossSectionArea: 0.0001131 m2; BarLength: 5.90418 m; Material: Steel

# IfcReinforcingBarType, no part of this type: type
PredefinedType: MAIN; NominalDiameter: 0.012 m; CrossSectionArea: 0.0001131 m2; BarLength: 5.76721 m; Material: Steel

# IfcReinforcingBarType, no part of this type: type
PredefinedType: MAIN; NominalDiameter: 0.012 m; CrossSectionArea: 0.0001131 m2; BarLength: 10.9172 m; Material: Steel

# IfcReinforcingBarType, no part of this type: type
PredefinedType: MAIN; NominalDiameter: 0.012 m; CrossSectionArea: 0.0001131 m2; BarLength: 0.73963 m; Material: Steel

# IfcReinforcingBarType, no part of this type: type
PredefinedType: MAIN; NominalDiameter: 0.012 m; CrossSectionArea: 0.0001131 m2; BarLength: 0.437046 m; Material: Steel

# IfcReinforcingBarType, no part of this type: type
PredefinedType: MAIN; NominalDiameter: 0.016 m; CrossSectionArea: 0.00020106 m2; BarLength: 1.72591 m; Material: Steel

# IfcReinforcingBarType, no part of this type: type
PredefinedType: MAIN; NominalDiameter: 0.016 m; CrossSectionArea: 0.00020106 m2; BarLength: 0.582727 m; Material: Steel

# IfcReinforcingBarType, no part of this type: type
PredefinedType: MAIN; NominalDiameter: 0.016 m; CrossSectionArea: 0.00020106 m2; BarLength: 0.461142 m; Material: Steel

# IfcReinforcingBarType, no part of this type: type
PredefinedType: MAIN; NominalDiameter: 0.016 m; CrossSectionArea: 0.00020106 m2; BarLength: 1.83017 m; Material: Steel

# IfcReinforcingBarType, no part of this type: type
PredefinedType: MAIN; NominalDiameter: 0.016 m; CrossSectionArea: 0.00020106 m2; BarLength: 2.99591 m; Material: Steel

# IfcReinforcingBarType, no part of this type: type
PredefinedType: MAIN; NominalDiameter: 0.012 m; CrossSectionArea: 0.0001131 m2; BarLength: 1.58591 m; Material: Steel

# IfcReinforcingBarType, no part of this type: type
PredefinedType: MAIN; NominalDiameter: 0.02 m; CrossSectionArea: 0.00031416 m2; BarLength: 2.86318 m; Material: Steel

# IfcReinforcingBarType, no part of this type: type
PredefinedType: MAIN; NominalDiameter: 0.02 m; CrossSectionArea: 0.00031416 m2; BarLength: 0.728409 m; Material: Steel

# IfcReinforcingBarType, no part of this type: type
PredefinedType: MAIN; NominalDiameter: 0.016 m; CrossSectionArea: 0.00020106 m2; BarLength: 0.827482 m; Material: Steel

# IfcReinforcingBarType, no part of this type: type
PredefinedType: MAIN; NominalDiameter: 0.012 m; CrossSectionArea: 0.0001131 m2; BarLength: 1.39591 m; Material: Steel

# IfcReinforcingBarType, no part of this type: type
PredefinedType: MAIN; NominalDiameter: 0.016 m; CrossSectionArea: 0.00020106 m2; BarLength: 1.30591 m; Material: Steel

# IfcReinforcingBarType, no part of this type: type
PredefinedType: MAIN; NominalDiameter: 0.016 m; CrossSectionArea: 0.00020106 m2; BarLength: 1.69591 m; Material: Steel

# IfcReinforcingBarType, no part of this type: type
PredefinedType: MAIN; NominalDiameter: 0.012 m; CrossSectionArea: 0.0001131 m2; BarLength: 1.36591 m; Material: Steel

# IfcReinforcingBarType, no part of this type: type
PredefinedType: MAIN; NominalDiameter: 0.012 m; CrossSectionArea: 0.0001131 m2; BarLength: 0.424888 m; Material: Steel

# IfcReinforcingBarType, no part of this type: type
PredefinedType: MAIN; NominalDiameter: 0.012 m; CrossSectionArea: 0.0001131 m2; BarLength: 0.467344 m; Material: Steel

# IfcReinforcingBarType, no part of this type: type
PredefinedType: MAIN; NominalDiameter: 0.012 m; CrossSectionArea: 0.0001131 m2; BarLength: 0.876429 m; Material: Steel

# IfcReinforcingBarType, no part of this type: type
PredefinedType: MAIN; NominalDiameter: 0.012 m; CrossSectionArea: 0.0001131 m2; BarLength: 0.462548 m; Material: Steel

# IfcReinforcingBarType, no part of this type: type
PredefinedType: MAIN; NominalDiameter: 0.016 m; CrossSectionArea: 0.00020106 m2; BarLength: 0.551757 m; Material: Steel

# IfcReinforcingBarType, no part of this type: type
PredefinedType: MAIN; NominalDiameter: 0.012 m; CrossSectionArea: 0.0001131 m2; BarLength: 1.09591 m; Material: Steel

# IfcReinforcingBarType, no part of this type: type
PredefinedType: MAIN; NominalDiameter: 0.012 m; CrossSectionArea: 0.0001131 m2; BarLength: 1.61591 m; Material: Steel

# IfcReinforcingBarType, no part of this type: type
PredefinedType: MAIN; NominalDiameter: 0.012 m; CrossSectionArea: 0.0001131 m2; BarLength: 0.433676 m; Material: Steel

# IfcReinforcingBarType, no part of this type: type
PredefinedType: MAIN; NominalDiameter: 0.012 m; CrossSectionArea: 0.0001131 m2; BarLength: 0.858311 m; Material: Steel

# IfcReinforcingBarType, no part of this type: type
PredefinedType: MAIN; NominalDiameter: 0.012 m; CrossSectionArea: 0.0001131 m2; BarLength: 0.476277 m; Material: Steel

# IfcReinforcingBarType, no part of this type: type
PredefinedType: MAIN; NominalDiameter: 0.012 m; CrossSectionArea: 0.0001131 m2; BarLength: 0.48324 m; Material: Steel

# IfcReinforcingBarType, no part of this type: type
PredefinedType: MAIN; NominalDiameter: 0.016 m; CrossSectionArea: 0.00020106 m2; BarLength: 0.881223 m; Material: Steel

# IfcReinforcingBarType, no part of this type: type
PredefinedType: MAIN; NominalDiameter: 0.012 m; CrossSectionArea: 0.0001131 m2; BarLength: 0.471284 m; Material: Steel

# IfcReinforcingBarType, no part of this type: type
PredefinedType: MAIN; NominalDiameter: 0.012 m; CrossSectionArea: 0.0001131 m2; BarLength: 0.830613 m; Material: Steel

# IfcReinforcingBarType, no part of this type: type
PredefinedType: MAIN; NominalDiameter: 0.01 m; CrossSectionArea: 0.00007854 m2; BarLength: 0.16 m; Material: Steel

# IfcReinforcingBarType, no part of this type: type
PredefinedType: MAIN; NominalDiameter: 0.03 m; CrossSectionArea: 0.00070686 m2; BarLength: 0.00499988 m; Material: Steel

# IfcReinforcingBarType, no part of this type: type
PredefinedType: MAIN; NominalDiameter: 0.012 m; CrossSectionArea: 0.0001131 m2; BarLength: 2.16321 m; Material: Steel

# IfcReinforcingBarType, no part of this type: type
PredefinedType: MAIN; NominalDiameter: 0.012 m; CrossSectionArea: 0.0001131 m2; BarLength: 1.4266 m; Material: Steel

# IfcReinforcingBarType, no part of this type: type
PredefinedType: MAIN; NominalDiameter: 0.012 m; CrossSectionArea: 0.0001131 m2; BarLength: 1.52661 m; Material: Steel

# IfcReinforcingBarType, no part of this type: type
PredefinedType: MAIN; NominalDiameter: 0.012 m; CrossSectionArea: 0.0001131 m2; BarLength: 1.4766 m; Material: Steel

# IfcReinforcingBarType, no part of this type: type
PredefinedType: MAIN; NominalDiameter: 0.012 m; CrossSectionArea: 0.0001131 m2; BarLength: 1.42661 m; Material: Steel

# IfcReinforcingBarType, no part of this type: type
PredefinedType: MAIN; NominalDiameter: 0.012 m; CrossSectionArea: 0.0001131 m2; BarLength: 2.36321 m; Material: Steel

# IfcReinforcingBarType, no part of this type: type
PredefinedType: MAIN; NominalDiameter: 0.012 m; CrossSectionArea: 0.0001131 m2; BarLength: 1.67661 m; Material: Steel

# IfcReinforcingBarType, no part of this type: type
PredefinedType: MAIN; NominalDiameter: 0.012 m; CrossSectionArea: 0.0001131 m2; BarLength: 7.15721 m; Material: Steel

# IfcReinforcingBarType, no part of this type: type
PredefinedType: MAIN; NominalDiameter: 0.012 m; CrossSectionArea: 0.0001131 m2; BarLength: 7.61721 m; Material: Steel

# IfcReinforcingBarType, no part of this type: type
PredefinedType: MAIN; NominalDiameter: 0.012 m; CrossSectionArea: 0.0001131 m2; BarLength: 14.4872 m; Material: Steel

# IfcReinforcingBarType, no part of this type: type
PredefinedType: MAIN; NominalDiameter: 0.012 m; CrossSectionArea: 0.0001131 m2; BarLength: 8.18721 m; Material: Steel

# IfcReinforcingBarType, no part of this type: type
PredefinedType: MAIN; NominalDiameter: 0.012 m; CrossSectionArea: 0.0001131 m2; BarLength: 5.98721 m; Material: Steel

# IfcReinforcingBarType, no part of this type: type
PredefinedType: MAIN; NominalDiameter: 0.012 m; CrossSectionArea: 0.0001131 m2; BarLength: 6.10721 m; Material: Steel

# IfcReinforcingBarType, no part of this type: type
PredefinedType: MAIN; NominalDiameter: 0.012 m; CrossSectionArea: 0.0001131 m2; BarLength: 11.7072 m; Material: Steel

# IfcReinforcingBarType, no part of this type: type
PredefinedType: MAIN; NominalDiameter: 0.012 m; CrossSectionArea: 0.0001131 m2; BarLength: 9.88721 m; Material: Steel

# IfcReinforcingBarType, no part of this type: type
PredefinedType: MAIN; NominalDiameter: 0.012 m; CrossSectionArea: 0.0001131 m2; BarLength: 1.20721 m; Material: Steel

# IfcReinforcingBarType, no part of this type: type
PredefinedType: MAIN; NominalDiameter: 0.012 m; CrossSectionArea: 0.0001131 m2; BarLength: 0.603401 m; Material: Steel

# IfcReinforcingBarType, no part of this type: type
PredefinedType: MAIN; NominalDiameter: 0.012 m; CrossSectionArea: 0.0001131 m2; BarLength: 1.06591 m; Material: Steel

# IfcReinforcingBarType, no part of this type: type
PredefinedType: MAIN; NominalDiameter: 0.012 m; CrossSectionArea: 0.0001131 m2; BarLength: 0.437046 m; Material: Steel

# IfcReinforcingBarType, no part of this type: type
PredefinedType: MAIN; NominalDiameter: 0.012 m; CrossSectionArea: 0.0001131 m2; BarLength: 0.885909 m; Material: Steel

# IfcReinforcingBarType, no part of this type: type
PredefinedType: MAIN; NominalDiameter: 0.012 m; CrossSectionArea: 0.0001131 m2; BarLength: 1.12591 m; Material: Steel

# IfcReinforcingBarType, no part of this type: type
PredefinedType: MAIN; NominalDiameter: 0.012 m; CrossSectionArea: 0.0001131 m2; BarLength: 1.81395 m; Material: Steel

# IfcReinforcingBarType, no part of this type: type
PredefinedType: MAIN; NominalDiameter: 0.012 m; CrossSectionArea: 0.0001131 m2; BarLength: 2.11591 m; Material: Steel

# IfcReinforcingBarType, no part of this type: type
PredefinedType: MAIN; NominalDiameter: 0.012 m; CrossSectionArea: 0.0001131 m2; BarLength: 0.815909 m; Material: Steel

# IfcReinforcingBarType, no part of this type: type
PredefinedType: MAIN; NominalDiameter: 0.012 m; CrossSectionArea: 0.0001131 m2; BarLength: 0.781222 m; Material: Steel

# IfcReinforcingBarType, no part of this type: type
PredefinedType: MAIN; NominalDiameter: 0.012 m; CrossSectionArea: 0.0001131 m2; BarLength: 0.783555 m; Material: Steel

# IfcReinforcingBarType, no part of this type: type
PredefinedType: MAIN; NominalDiameter: 0.012 m; CrossSectionArea: 0.0001131 m2; BarLength: 0.785886 m; Material: Steel

# IfcReinforcingBarType, no part of this type: type
PredefinedType: MAIN; NominalDiameter: 0.012 m; CrossSectionArea: 0.0001131 m2; BarLength: 0.133206 m; Material: Steel

# IfcReinforcingBarType, no part of this type: type
PredefinedType: MAIN; NominalDiameter: 0.012 m; CrossSectionArea: 0.0001131 m2; BarLength: 0.955909 m; Material: Steel

# IfcReinforcingBarType, no part of this type: type
PredefinedType: MAIN; NominalDiameter: 0.012 m; CrossSectionArea: 0.0001131 m2; BarLength: 0.387218 m; Material: Steel

# IfcReinforcingBarType, no part of this type: type
PredefinedType: MAIN; NominalDiameter: 0.01 m; CrossSectionArea: 0.00007854 m2; BarLength: 0.16 m; Material: Steel

# IfcReinforcingBarType, no part of this type: type
PredefinedType: MAIN; NominalDiameter: 0.03 m; CrossSectionArea: 0.00070686 m2; BarLength: 0.00500011 m; Material: Steel

# IfcReinforcingBarType, no part of this type: type
PredefinedType: MAIN; NominalDiameter: 0.016 m; CrossSectionArea: 0.00020106 m2; BarLength: 6.20721 m; Material: Steel

# IfcReinforcingBarType, no part of this type: type
PredefinedType: MAIN; NominalDiameter: 0.012 m; CrossSectionArea: 0.0001131 m2; BarLength: 8.5871 m; Material: Steel

# IfcReinforcingBarType, no part of this type: type
PredefinedType: MAIN; NominalDiameter: 0.012 m; CrossSectionArea: 0.0001131 m2; BarLength: 6.23121 m; Material: Steel

# IfcReinforcingBarType, no part of this type: type
PredefinedType: MAIN; NominalDiameter: 0.01 m; CrossSectionArea: 0.00007854 m2; BarLength: 8.6051 m; Material: Steel

# IfcReinforcingBarType, no part of this type: type
PredefinedType: LIGATURE; NominalDiameter: 0.008 m; CrossSectionArea: 0.000050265 m2; BarLength: 0.986828 m; Material: Steel

# IfcReinforcingBarType, no part of this type: type
PredefinedType: MAIN; NominalDiameter: 0.016 m; CrossSectionArea: 0.00020106 m2; BarLength: 2.30621 m; Material: Steel

# Material: Calcestruzzo classe C25/30
Calcestruzzo classe C25/30 - Mass Density: 2500; Poisson Ratio: 0.1; Shear Modulus: 1429420032; Thermal Expansion Coefficient: 0.00001; Young Modulus: 3144719872

# Material: Calcestruzzo classe C25/30
Calcestruzzo classe C25/30 - Mass Density: 2500; Poisson Ratio: 0.1; Shear Modulus: 1429420032; Thermal Expansion Coefficient: 0.00001; Young Modulus: 3144719872

# Material: Calcestruzzo classe C25/30
Calcestruzzo classe C25/30 - Mass Density: 2500; Poisson Ratio: 0.1; Shear Modulus: 1429420032; Thermal Expansion Coefficient: 0.00001; Young Modulus: 3144719872

# Material: Calcestruzzo classe C25/30
Calcestruzzo classe C25/30 - Mass Density: 2500; Poisson Ratio: 0.1; Shear Modulus: 1429420032; Thermal Expansion Coefficient: 0.00001; Young Modulus: 3144719872

# Material: Calcestruzzo classe C25/30
Calcestruzzo classe C25/30 - Mass Density: 2500; Poisson Ratio: 0.1; Shear Modulus: 1429420032; Thermal Expansion Coefficient: 0.00001; Young Modulus: 3144719872

# Material: Calcestruzzo classe C25/30
Calcestruzzo classe C25/30 - Mass Density: 2500; Poisson Ratio: 0.1; Shear Modulus: 1429420032; Thermal Expansion Coefficient: 0.00001; Young Modulus: 3144719872

# Material: Calcestruzzo classe C25/30
Calcestruzzo classe C25/30 - Mass Density: 2500; Poisson Ratio: 0.1; Shear Modulus: 1429420032; Thermal Expansion Coefficient: 0.00001; Young Modulus: 3144719872

# Material: Calcestruzzo classe C25/30
Calcestruzzo classe C25/30 - Mass Density: 2500; Poisson Ratio: 0.1; Shear Modulus: 1429420032; Thermal Expansion Coefficient: 0.00001; Young Modulus: 3144719872

# Material: Calcestruzzo classe C25/30
Calcestruzzo classe C25/30 - Mass Density: 2500; Poisson Ratio: 0.1; Shear Modulus: 1429420032; Thermal Expansion Coefficient: 0.00001; Young Modulus: 3144719872

# Material: Calcestruzzo classe C25/30
Calcestruzzo classe C25/30 - Mass Density: 2500; Poisson Ratio: 0.1; Shear Modulus: 1429420032; Thermal Expansion Coefficient: 0.00001; Young Modulus: 3144719872

# Material: Calcestruzzo classe C25/30
Calcestruzzo classe C25/30 - Mass Density: 2500; Poisson Ratio: 0.1; Shear Modulus: 1429420032; Thermal Expansion Coefficient: 0.00001; Young Modulus: 3144719872

# Material: Calcestruzzo classe C25/30
Calcestruzzo classe C25/30 - Mass Density: 2500; Poisson Ratio: 0.1; Shear Modulus: 1429420032; Thermal Expansion Coefficient: 0.00001; Young Modulus: 3144719872

# Material: Calcestruzzo classe C25/30
Calcestruzzo classe C25/30 - Mass Density: 2500; Poisson Ratio: 0.1; Shear Modulus: 1429420032; Thermal Expansion Coefficient: 0.00001; Young Modulus: 3144719872

# Material: Calcestruzzo classe C25/30
Calcestruzzo classe C25/30 - Mass Density: 2500; Poisson Ratio: 0.1; Shear Modulus: 1429420032; Thermal Expansion Coefficient: 0.00001; Young Modulus: 3144719872

# Material: Calcestruzzo classe C25/30
Calcestruzzo classe C25/30 - Mass Density: 2500; Poisson Ratio: 0.1; Shear Modulus: 1429420032; Thermal Expansion Coefficient: 0.00001; Young Modulus: 3144719872

# Material: Calcestruzzo classe C25/30
Calcestruzzo classe C25/30 - Mass Density: 2500; Poisson Ratio: 0.1; Shear Modulus: 1429420032; Thermal Expansion Coefficient: 0.00001; Young Modulus: 3144719872

# Material: Calcestruzzo classe C25/30
Calcestruzzo classe C25/30 - Mass Density: 2500; Poisson Ratio: 0.1; Shear Modulus: 1429420032; Thermal Expansion Coefficient: 0.00001; Young Modulus: 3144719872

# Material: Calcestruzzo classe C25/30
Calcestruzzo classe C25/30 - Mass Density: 2500; Poisson Ratio: 0.1; Shear Modulus: 1429420032; Thermal Expansion Coefficient: 0.00001; Young Modulus: 3144719872

# Material: Calcestruzzo classe C25/30
Calcestruzzo classe C25/30 - Mass Density: 2500; Poisson Ratio: 0.1; Shear Modulus: 1429420032; Thermal Expansion Coefficient: 0.00001; Young Modulus: 3144719872

# Material: Calcestruzzo classe C25/30
Calcestruzzo classe C25/30 - Mass Density: 2500; Poisson Ratio: 0.1; Shear Modulus: 1429420032; Thermal Expansion Coefficient: 0.00001; Young Modulus: 3144719872

# Material: Calcestruzzo classe C25/30
Calcestruzzo classe C25/30 - Mass Density: 2500; Poisson Ratio: 0.1; Shear Modulus: 1429420032; Thermal Expansion Coefficient: 0.00001; Young Modulus: 3144719872

# Material: Calcestruzzo classe C25/30
Calcestruzzo classe C25/30 - Mass Density: 2500; Poisson Ratio: 0.1; Shear Modulus: 1429420032; Thermal Expansion Coefficient: 0.00001; Young Modulus: 3144719872

# Material: Calcestruzzo classe C25/30
Calcestruzzo classe C25/30 - Mass Density: 2500; Poisson Ratio: 0.1; Shear Modulus: 1429420032; Thermal Expansion Coefficient: 0.00001; Young Modulus: 3144719872

# Material: Calcestruzzo classe C25/30
Calcestruzzo classe C25/30 - Mass Density: 2500; Poisson Ratio: 0.1; Shear Modulus: 1429420032; Thermal Expansion Coefficient: 0.00001; Young Modulus: 3144719872

# Material: Calcestruzzo classe C25/30
Calcestruzzo classe C25/30 - Mass Density: 2500; Poisson Ratio: 0.1; Shear Modulus: 1429420032; Thermal Expansion Coefficient: 0.00001; Young Modulus: 3144719872

# Material: Calcestruzzo classe C25/30
Calcestruzzo classe C25/30 - Mass Density: 2500; Poisson Ratio: 0.1; Shear Modulus: 1429420032; Thermal Expansion Coefficient: 0.00001; Young Modulus: 3144719872

# Material: Calcestruzzo classe C25/30
Calcestruzzo classe C25/30 - Mass Density: 2500; Poisson Ratio: 0.1; Shear Modulus: 1429420032; Thermal Expansion Coefficient: 0.00001; Young Modulus: 3144719872
